One B-rep face of a CAD part: STEP entity #1161.
In plain terms, the planar face has unit normal (0, 1, 0).
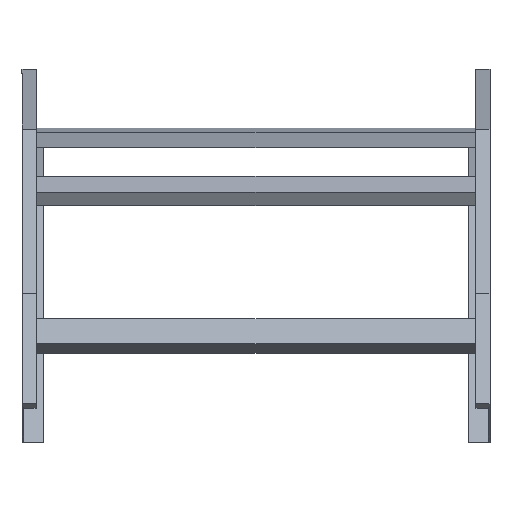
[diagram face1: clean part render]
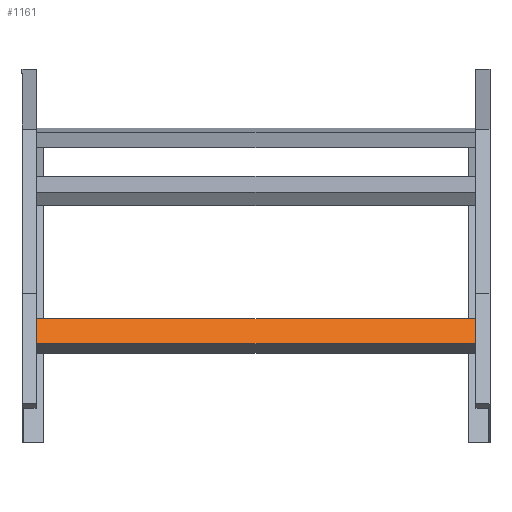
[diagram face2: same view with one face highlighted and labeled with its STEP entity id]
Its self-contained STEP definition (entity closure, numbers rounded to 3 decimals):
#21 = VERTEX_POINT ( 'NONE', #313 ) ;
#176 = VERTEX_POINT ( 'NONE', #251 ) ;
#202 = VECTOR ( 'NONE', #1524, 1000. ) ;
#213 = LINE ( 'NONE', #1114, #202 ) ;
#225 = PLANE ( 'NONE',  #1022 ) ;
#248 = FACE_OUTER_BOUND ( 'NONE', #1501, .T. ) ;
#251 = CARTESIAN_POINT ( 'NONE',  ( -298., 20., 20.25 ) ) ;
#272 = CARTESIAN_POINT ( 'NONE',  ( -298., 20., 20.25 ) ) ;
#275 = CARTESIAN_POINT ( 'NONE',  ( -298., 20., -20.25 ) ) ;
#309 = EDGE_CURVE ( 'NONE', #1141, #176, #1429, .T. ) ;
#313 = CARTESIAN_POINT ( 'NONE',  ( 298., 20., -20.25 ) ) ;
#450 = EDGE_CURVE ( 'NONE', #21, #529, #755, .T. ) ;
#497 = DIRECTION ( 'NONE',  ( 0., -1., 0. ) ) ;
#529 = VERTEX_POINT ( 'NONE', #1207 ) ;
#571 = DIRECTION ( 'NONE',  ( -1., 0., 0. ) ) ;
#618 = ORIENTED_EDGE ( 'NONE', *, *, #1229, .F. ) ;
#736 = VECTOR ( 'NONE', #769, 1000. ) ;
#755 = LINE ( 'NONE', #795, #1484 ) ;
#769 = DIRECTION ( 'NONE',  ( 0., 0., 1. ) ) ;
#795 = CARTESIAN_POINT ( 'NONE',  ( 298., 20., 20.25 ) ) ;
#842 = LINE ( 'NONE', #1352, #1384 ) ;
#898 = DIRECTION ( 'NONE',  ( 0., 0., 1. ) ) ;
#993 = DIRECTION ( 'NONE',  ( 0., 0., -1. ) ) ;
#1022 = AXIS2_PLACEMENT_3D ( 'NONE', #1661, #497, #993 ) ;
#1114 = CARTESIAN_POINT ( 'NONE',  ( 298., 20., -20.25 ) ) ;
#1141 = VERTEX_POINT ( 'NONE', #275 ) ;
#1161 = ADVANCED_FACE ( 'NONE', ( #248 ), #225, .F. ) ;
#1207 = CARTESIAN_POINT ( 'NONE',  ( 298., 20., 20.25 ) ) ;
#1229 = EDGE_CURVE ( 'NONE', #529, #176, #842, .T. ) ;
#1283 = ORIENTED_EDGE ( 'NONE', *, *, #450, .F. ) ;
#1352 = CARTESIAN_POINT ( 'NONE',  ( 298., 20., 20.25 ) ) ;
#1384 = VECTOR ( 'NONE', #571, 1000. ) ;
#1429 = LINE ( 'NONE', #272, #736 ) ;
#1484 = VECTOR ( 'NONE', #898, 1000. ) ;
#1501 = EDGE_LOOP ( 'NONE', ( #1559, #618, #1283, #1531 ) ) ;
#1524 = DIRECTION ( 'NONE',  ( -1., 0., 0. ) ) ;
#1531 = ORIENTED_EDGE ( 'NONE', *, *, #1580, .T. ) ;
#1559 = ORIENTED_EDGE ( 'NONE', *, *, #309, .T. ) ;
#1580 = EDGE_CURVE ( 'NONE', #21, #1141, #213, .T. ) ;
#1661 = CARTESIAN_POINT ( 'NONE',  ( 298., 20., 20.25 ) ) ;
